VERSION 5.7 ;
  NAMESCASESENSITIVE ON ;
  NOWIREEXTENSIONATPIN ON ;
  DIVIDERCHAR "/" ;
  BUSBITCHARS "[]" ;
UNITS
  DATABASE MICRONS 200 ;
END UNITS

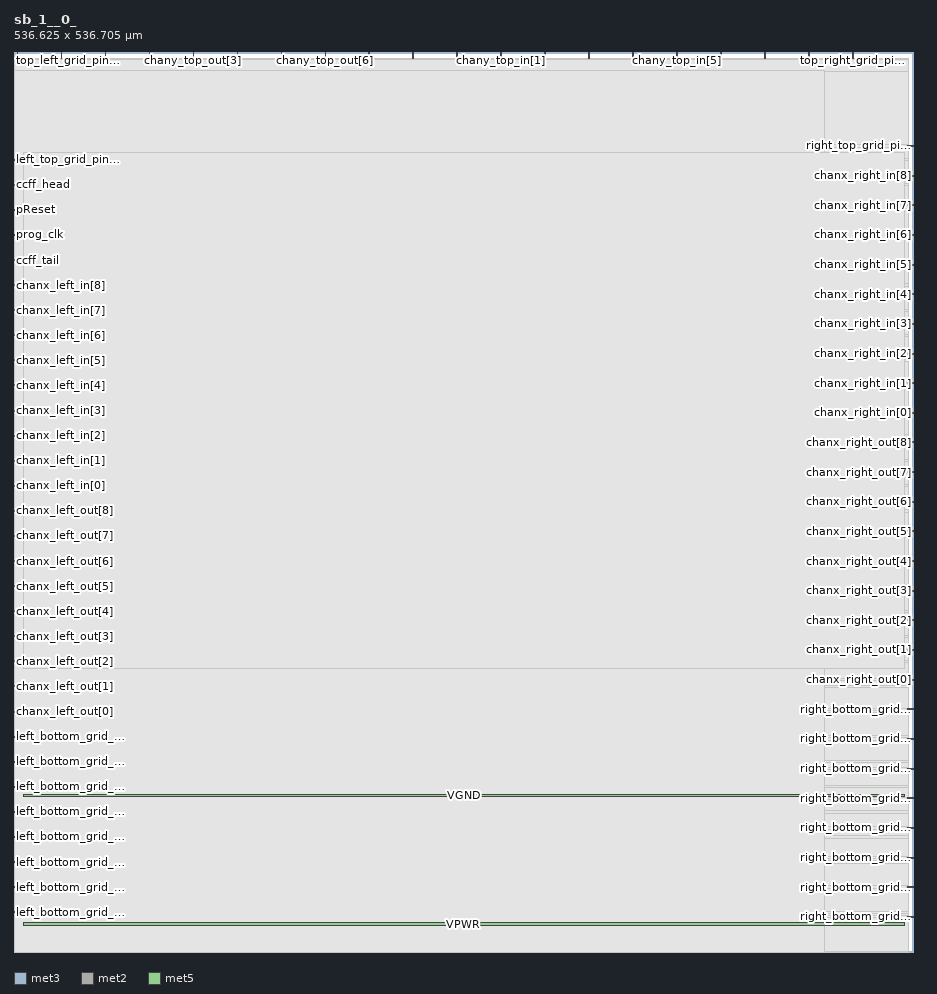
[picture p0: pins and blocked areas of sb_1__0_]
MACRO sb_1__0_
  CLASS BLOCK ;
  FOREIGN sb_1__0_ ;
  ORIGIN 0.000 0.000 ;
  SIZE 536.625 BY 536.705 ;
  PIN left_bottom_grid_pin_1_
    DIRECTION INPUT ;
    PORT
      LAYER met3 ;
        RECT 0.000 23.400 4.000 24.000 ;
    END
  END left_bottom_grid_pin_1_
  PIN left_bottom_grid_pin_3_
    DIRECTION INPUT ;
    PORT
      LAYER met3 ;
        RECT 0.000 38.360 4.000 38.960 ;
    END
  END left_bottom_grid_pin_3_
  PIN left_bottom_grid_pin_5_
    DIRECTION INPUT ;
    PORT
      LAYER met3 ;
        RECT 0.000 53.320 4.000 53.920 ;
    END
  END left_bottom_grid_pin_5_
  PIN left_bottom_grid_pin_7_
    DIRECTION INPUT ;
    PORT
      LAYER met3 ;
        RECT 0.000 68.280 4.000 68.880 ;
    END
  END left_bottom_grid_pin_7_
  PIN left_bottom_grid_pin_9_
    DIRECTION INPUT ;
    PORT
      LAYER met3 ;
        RECT 0.000 83.240 4.000 83.840 ;
    END
  END left_bottom_grid_pin_9_
  PIN left_bottom_grid_pin_11_
    DIRECTION INPUT ;
    PORT
      LAYER met3 ;
        RECT 0.000 98.200 4.000 98.800 ;
    END
  END left_bottom_grid_pin_11_
  PIN left_bottom_grid_pin_13_
    DIRECTION INPUT ;
    PORT
      LAYER met3 ;
        RECT 0.000 113.160 4.000 113.760 ;
    END
  END left_bottom_grid_pin_13_
  PIN left_bottom_grid_pin_15_
    DIRECTION INPUT ;
    PORT
      LAYER met3 ;
        RECT 0.000 128.120 4.000 128.720 ;
    END
  END left_bottom_grid_pin_15_
  PIN chanx_left_out[0]
    DIRECTION OUTPUT TRISTATE ;
    PORT
      LAYER met3 ;
        RECT 0.000 143.080 4.000 143.680 ;
    END
  END chanx_left_out[0]
  PIN chanx_left_out[1]
    DIRECTION OUTPUT TRISTATE ;
    PORT
      LAYER met3 ;
        RECT 0.000 158.040 4.000 158.640 ;
    END
  END chanx_left_out[1]
  PIN chanx_left_out[2]
    DIRECTION OUTPUT TRISTATE ;
    PORT
      LAYER met3 ;
        RECT 0.000 173.000 4.000 173.600 ;
    END
  END chanx_left_out[2]
  PIN chanx_left_out[3]
    DIRECTION OUTPUT TRISTATE ;
    PORT
      LAYER met3 ;
        RECT 0.000 187.960 4.000 188.560 ;
    END
  END chanx_left_out[3]
  PIN chanx_left_out[4]
    DIRECTION OUTPUT TRISTATE ;
    PORT
      LAYER met3 ;
        RECT 0.000 202.920 4.000 203.520 ;
    END
  END chanx_left_out[4]
  PIN chanx_left_out[5]
    DIRECTION OUTPUT TRISTATE ;
    PORT
      LAYER met3 ;
        RECT 0.000 217.880 4.000 218.480 ;
    END
  END chanx_left_out[5]
  PIN chanx_left_out[6]
    DIRECTION OUTPUT TRISTATE ;
    PORT
      LAYER met3 ;
        RECT 0.000 232.840 4.000 233.440 ;
    END
  END chanx_left_out[6]
  PIN chanx_left_out[7]
    DIRECTION OUTPUT TRISTATE ;
    PORT
      LAYER met3 ;
        RECT 0.000 247.800 4.000 248.400 ;
    END
  END chanx_left_out[7]
  PIN chanx_left_out[8]
    DIRECTION OUTPUT TRISTATE ;
    PORT
      LAYER met3 ;
        RECT 0.000 262.760 4.000 263.360 ;
    END
  END chanx_left_out[8]
  PIN chanx_left_in[0]
    DIRECTION INPUT ;
    PORT
      LAYER met3 ;
        RECT 0.000 277.720 4.000 278.320 ;
    END
  END chanx_left_in[0]
  PIN chanx_left_in[1]
    DIRECTION INPUT ;
    PORT
      LAYER met3 ;
        RECT 0.000 292.680 4.000 293.280 ;
    END
  END chanx_left_in[1]
  PIN chanx_left_in[2]
    DIRECTION INPUT ;
    PORT
      LAYER met3 ;
        RECT 0.000 307.640 4.000 308.240 ;
    END
  END chanx_left_in[2]
  PIN chanx_left_in[3]
    DIRECTION INPUT ;
    PORT
      LAYER met3 ;
        RECT 0.000 322.600 4.000 323.200 ;
    END
  END chanx_left_in[3]
  PIN chanx_left_in[4]
    DIRECTION INPUT ;
    PORT
      LAYER met3 ;
        RECT 0.000 337.560 4.000 338.160 ;
    END
  END chanx_left_in[4]
  PIN chanx_left_in[5]
    DIRECTION INPUT ;
    PORT
      LAYER met3 ;
        RECT 0.000 352.520 4.000 353.120 ;
    END
  END chanx_left_in[5]
  PIN chanx_left_in[6]
    DIRECTION INPUT ;
    PORT
      LAYER met3 ;
        RECT 0.000 367.480 4.000 368.080 ;
    END
  END chanx_left_in[6]
  PIN chanx_left_in[7]
    DIRECTION INPUT ;
    PORT
      LAYER met3 ;
        RECT 0.000 382.440 4.000 383.040 ;
    END
  END chanx_left_in[7]
  PIN chanx_left_in[8]
    DIRECTION INPUT ;
    PORT
      LAYER met3 ;
        RECT 0.000 397.400 4.000 398.000 ;
    END
  END chanx_left_in[8]
  PIN ccff_tail
    DIRECTION OUTPUT TRISTATE ;
    PORT
      LAYER met3 ;
        RECT 0.000 412.360 4.000 412.960 ;
    END
  END ccff_tail
  PIN prog_clk
    DIRECTION INPUT ;
    PORT
      LAYER met3 ;
        RECT 0.000 427.320 4.000 427.920 ;
    END
  END prog_clk
  PIN pReset
    DIRECTION INPUT ;
    PORT
      LAYER met3 ;
        RECT 0.000 442.280 4.000 442.880 ;
    END
  END pReset
  PIN ccff_head
    DIRECTION INPUT ;
    PORT
      LAYER met3 ;
        RECT 0.000 457.240 4.000 457.840 ;
    END
  END ccff_head
  PIN left_top_grid_pin_10_
    DIRECTION OUTPUT TRISTATE ;
    PORT
      LAYER met3 ;
        RECT 0.000 472.200 4.000 472.800 ;
    END
  END left_top_grid_pin_10_
  PIN top_left_grid_pin_13_
    DIRECTION INPUT ;
    PORT
      LAYER met2 ;
        RECT 1.930 532.705 2.210 536.705 ;
    END
  END top_left_grid_pin_13_
  PIN chany_top_out[0]
    DIRECTION OUTPUT TRISTATE ;
    PORT
      LAYER met2 ;
        RECT 28.150 532.705 28.430 536.705 ;
    END
  END chany_top_out[0]
  PIN chany_top_out[1]
    DIRECTION OUTPUT TRISTATE ;
    PORT
      LAYER met2 ;
        RECT 54.370 532.705 54.650 536.705 ;
    END
  END chany_top_out[1]
  PIN chany_top_out[2]
    DIRECTION OUTPUT TRISTATE ;
    PORT
      LAYER met2 ;
        RECT 80.590 532.705 80.870 536.705 ;
    END
  END chany_top_out[2]
  PIN chany_top_out[3]
    DIRECTION OUTPUT TRISTATE ;
    PORT
      LAYER met2 ;
        RECT 106.810 532.705 107.090 536.705 ;
    END
  END chany_top_out[3]
  PIN chany_top_out[4]
    DIRECTION OUTPUT TRISTATE ;
    PORT
      LAYER met2 ;
        RECT 133.030 532.705 133.310 536.705 ;
    END
  END chany_top_out[4]
  PIN chany_top_out[5]
    DIRECTION OUTPUT TRISTATE ;
    PORT
      LAYER met2 ;
        RECT 159.250 532.705 159.530 536.705 ;
    END
  END chany_top_out[5]
  PIN chany_top_out[6]
    DIRECTION OUTPUT TRISTATE ;
    PORT
      LAYER met2 ;
        RECT 185.470 532.705 185.750 536.705 ;
    END
  END chany_top_out[6]
  PIN chany_top_out[7]
    DIRECTION OUTPUT TRISTATE ;
    PORT
      LAYER met2 ;
        RECT 211.690 532.705 211.970 536.705 ;
    END
  END chany_top_out[7]
  PIN chany_top_out[8]
    DIRECTION OUTPUT TRISTATE ;
    PORT
      LAYER met2 ;
        RECT 237.910 532.705 238.190 536.705 ;
    END
  END chany_top_out[8]
  PIN chany_top_in[0]
    DIRECTION INPUT ;
    PORT
      LAYER met2 ;
        RECT 264.130 532.705 264.410 536.705 ;
    END
  END chany_top_in[0]
  PIN chany_top_in[1]
    DIRECTION INPUT ;
    PORT
      LAYER met2 ;
        RECT 290.350 532.705 290.630 536.705 ;
    END
  END chany_top_in[1]
  PIN chany_top_in[2]
    DIRECTION INPUT ;
    PORT
      LAYER met2 ;
        RECT 316.570 532.705 316.850 536.705 ;
    END
  END chany_top_in[2]
  PIN chany_top_in[3]
    DIRECTION INPUT ;
    PORT
      LAYER met2 ;
        RECT 342.790 532.705 343.070 536.705 ;
    END
  END chany_top_in[3]
  PIN chany_top_in[4]
    DIRECTION INPUT ;
    PORT
      LAYER met2 ;
        RECT 369.010 532.705 369.290 536.705 ;
    END
  END chany_top_in[4]
  PIN chany_top_in[5]
    DIRECTION INPUT ;
    PORT
      LAYER met2 ;
        RECT 395.230 532.705 395.510 536.705 ;
    END
  END chany_top_in[5]
  PIN chany_top_in[6]
    DIRECTION INPUT ;
    PORT
      LAYER met2 ;
        RECT 421.450 532.705 421.730 536.705 ;
    END
  END chany_top_in[6]
  PIN chany_top_in[7]
    DIRECTION INPUT ;
    PORT
      LAYER met2 ;
        RECT 447.670 532.705 447.950 536.705 ;
    END
  END chany_top_in[7]
  PIN chany_top_in[8]
    DIRECTION INPUT ;
    PORT
      LAYER met2 ;
        RECT 473.890 532.705 474.170 536.705 ;
    END
  END chany_top_in[8]
  PIN top_right_grid_pin_11_
    DIRECTION INPUT ;
    PORT
      LAYER met2 ;
        RECT 500.110 532.705 500.390 536.705 ;
    END
  END top_right_grid_pin_11_
  PIN right_bottom_grid_pin_1_
    DIRECTION INPUT ;
    PORT
      LAYER met3 ;
        RECT 532.625 20.680 536.625 21.280 ;
    END
  END right_bottom_grid_pin_1_
  PIN right_bottom_grid_pin_3_
    DIRECTION INPUT ;
    PORT
      LAYER met3 ;
        RECT 532.625 38.360 536.625 38.960 ;
    END
  END right_bottom_grid_pin_3_
  PIN right_bottom_grid_pin_5_
    DIRECTION INPUT ;
    PORT
      LAYER met3 ;
        RECT 532.625 56.040 536.625 56.640 ;
    END
  END right_bottom_grid_pin_5_
  PIN right_bottom_grid_pin_7_
    DIRECTION INPUT ;
    PORT
      LAYER met3 ;
        RECT 532.625 73.720 536.625 74.320 ;
    END
  END right_bottom_grid_pin_7_
  PIN right_bottom_grid_pin_9_
    DIRECTION INPUT ;
    PORT
      LAYER met3 ;
        RECT 532.625 91.400 536.625 92.000 ;
    END
  END right_bottom_grid_pin_9_
  PIN right_bottom_grid_pin_11_
    DIRECTION INPUT ;
    PORT
      LAYER met3 ;
        RECT 532.625 109.080 536.625 109.680 ;
    END
  END right_bottom_grid_pin_11_
  PIN right_bottom_grid_pin_13_
    DIRECTION INPUT ;
    PORT
      LAYER met3 ;
        RECT 532.625 126.760 536.625 127.360 ;
    END
  END right_bottom_grid_pin_13_
  PIN right_bottom_grid_pin_15_
    DIRECTION INPUT ;
    PORT
      LAYER met3 ;
        RECT 532.625 144.440 536.625 145.040 ;
    END
  END right_bottom_grid_pin_15_
  PIN chanx_right_out[0]
    DIRECTION OUTPUT TRISTATE ;
    PORT
      LAYER met3 ;
        RECT 532.625 162.120 536.625 162.720 ;
    END
  END chanx_right_out[0]
  PIN chanx_right_out[1]
    DIRECTION OUTPUT TRISTATE ;
    PORT
      LAYER met3 ;
        RECT 532.625 179.800 536.625 180.400 ;
    END
  END chanx_right_out[1]
  PIN chanx_right_out[2]
    DIRECTION OUTPUT TRISTATE ;
    PORT
      LAYER met3 ;
        RECT 532.625 197.480 536.625 198.080 ;
    END
  END chanx_right_out[2]
  PIN chanx_right_out[3]
    DIRECTION OUTPUT TRISTATE ;
    PORT
      LAYER met3 ;
        RECT 532.625 215.160 536.625 215.760 ;
    END
  END chanx_right_out[3]
  PIN chanx_right_out[4]
    DIRECTION OUTPUT TRISTATE ;
    PORT
      LAYER met3 ;
        RECT 532.625 232.840 536.625 233.440 ;
    END
  END chanx_right_out[4]
  PIN chanx_right_out[5]
    DIRECTION OUTPUT TRISTATE ;
    PORT
      LAYER met3 ;
        RECT 532.625 250.520 536.625 251.120 ;
    END
  END chanx_right_out[5]
  PIN chanx_right_out[6]
    DIRECTION OUTPUT TRISTATE ;
    PORT
      LAYER met3 ;
        RECT 532.625 268.200 536.625 268.800 ;
    END
  END chanx_right_out[6]
  PIN chanx_right_out[7]
    DIRECTION OUTPUT TRISTATE ;
    PORT
      LAYER met3 ;
        RECT 532.625 285.880 536.625 286.480 ;
    END
  END chanx_right_out[7]
  PIN chanx_right_out[8]
    DIRECTION OUTPUT TRISTATE ;
    PORT
      LAYER met3 ;
        RECT 532.625 303.560 536.625 304.160 ;
    END
  END chanx_right_out[8]
  PIN chanx_right_in[0]
    DIRECTION INPUT ;
    PORT
      LAYER met3 ;
        RECT 532.625 321.240 536.625 321.840 ;
    END
  END chanx_right_in[0]
  PIN chanx_right_in[1]
    DIRECTION INPUT ;
    PORT
      LAYER met3 ;
        RECT 532.625 338.920 536.625 339.520 ;
    END
  END chanx_right_in[1]
  PIN chanx_right_in[2]
    DIRECTION INPUT ;
    PORT
      LAYER met3 ;
        RECT 532.625 356.600 536.625 357.200 ;
    END
  END chanx_right_in[2]
  PIN chanx_right_in[3]
    DIRECTION INPUT ;
    PORT
      LAYER met3 ;
        RECT 532.625 374.280 536.625 374.880 ;
    END
  END chanx_right_in[3]
  PIN chanx_right_in[4]
    DIRECTION INPUT ;
    PORT
      LAYER met3 ;
        RECT 532.625 391.960 536.625 392.560 ;
    END
  END chanx_right_in[4]
  PIN chanx_right_in[5]
    DIRECTION INPUT ;
    PORT
      LAYER met3 ;
        RECT 532.625 409.640 536.625 410.240 ;
    END
  END chanx_right_in[5]
  PIN chanx_right_in[6]
    DIRECTION INPUT ;
    PORT
      LAYER met3 ;
        RECT 532.625 427.320 536.625 427.920 ;
    END
  END chanx_right_in[6]
  PIN chanx_right_in[7]
    DIRECTION INPUT ;
    PORT
      LAYER met3 ;
        RECT 532.625 445.000 536.625 445.600 ;
    END
  END chanx_right_in[7]
  PIN chanx_right_in[8]
    DIRECTION INPUT ;
    PORT
      LAYER met3 ;
        RECT 532.625 462.680 536.625 463.280 ;
    END
  END chanx_right_in[8]
  PIN right_top_grid_pin_10_
    DIRECTION OUTPUT TRISTATE ;
    PORT
      LAYER met3 ;
        RECT 532.625 480.360 536.625 480.960 ;
    END
  END right_top_grid_pin_10_
  PIN VPWR
    DIRECTION INPUT ;
    USE POWER ;
    PORT
      LAYER met5 ;
        RECT 5.520 15.850 530.840 17.450 ;
    END
  END VPWR
  PIN VGND
    DIRECTION INPUT ;
    USE GROUND ;
    PORT
      LAYER met5 ;
        RECT 5.520 92.440 530.840 94.040 ;
    END
  END VGND
  OBS
      LAYER li1 ;
        RECT 5.520 0.155 530.840 525.285 ;
      LAYER met1 ;
        RECT 0.530 0.000 533.070 532.980 ;
      LAYER met2 ;
        RECT 0.090 532.425 1.650 533.090 ;
        RECT 2.490 532.425 27.870 533.090 ;
        RECT 28.710 532.425 54.090 533.090 ;
        RECT 54.930 532.425 80.310 533.090 ;
        RECT 81.150 532.425 106.530 533.090 ;
        RECT 107.370 532.425 132.750 533.090 ;
        RECT 133.590 532.425 158.970 533.090 ;
        RECT 159.810 532.425 185.190 533.090 ;
        RECT 186.030 532.425 211.410 533.090 ;
        RECT 212.250 532.425 237.630 533.090 ;
        RECT 238.470 532.425 263.850 533.090 ;
        RECT 264.690 532.425 290.070 533.090 ;
        RECT 290.910 532.425 316.290 533.090 ;
        RECT 317.130 532.425 342.510 533.090 ;
        RECT 343.350 532.425 368.730 533.090 ;
        RECT 369.570 532.425 394.950 533.090 ;
        RECT 395.790 532.425 421.170 533.090 ;
        RECT 422.010 532.425 447.390 533.090 ;
        RECT 448.230 532.425 473.610 533.090 ;
        RECT 474.450 532.425 499.830 533.090 ;
        RECT 500.670 532.425 533.510 533.090 ;
        RECT 0.090 0.000 533.510 532.425 ;
      LAYER met3 ;
        RECT 0.065 481.360 533.290 525.365 ;
        RECT 0.065 479.960 532.225 481.360 ;
        RECT 0.065 473.200 533.290 479.960 ;
        RECT 4.400 471.800 533.290 473.200 ;
        RECT 0.065 463.680 533.290 471.800 ;
        RECT 0.065 462.280 532.225 463.680 ;
        RECT 0.065 458.240 533.290 462.280 ;
        RECT 4.400 456.840 533.290 458.240 ;
        RECT 0.065 446.000 533.290 456.840 ;
        RECT 0.065 444.600 532.225 446.000 ;
        RECT 0.065 443.280 533.290 444.600 ;
        RECT 4.400 441.880 533.290 443.280 ;
        RECT 0.065 428.320 533.290 441.880 ;
        RECT 4.400 426.920 532.225 428.320 ;
        RECT 0.065 413.360 533.290 426.920 ;
        RECT 4.400 411.960 533.290 413.360 ;
        RECT 0.065 410.640 533.290 411.960 ;
        RECT 0.065 409.240 532.225 410.640 ;
        RECT 0.065 398.400 533.290 409.240 ;
        RECT 4.400 397.000 533.290 398.400 ;
        RECT 0.065 392.960 533.290 397.000 ;
        RECT 0.065 391.560 532.225 392.960 ;
        RECT 0.065 383.440 533.290 391.560 ;
        RECT 4.400 382.040 533.290 383.440 ;
        RECT 0.065 375.280 533.290 382.040 ;
        RECT 0.065 373.880 532.225 375.280 ;
        RECT 0.065 368.480 533.290 373.880 ;
        RECT 4.400 367.080 533.290 368.480 ;
        RECT 0.065 357.600 533.290 367.080 ;
        RECT 0.065 356.200 532.225 357.600 ;
        RECT 0.065 353.520 533.290 356.200 ;
        RECT 4.400 352.120 533.290 353.520 ;
        RECT 0.065 339.920 533.290 352.120 ;
        RECT 0.065 338.560 532.225 339.920 ;
        RECT 4.400 338.520 532.225 338.560 ;
        RECT 4.400 337.160 533.290 338.520 ;
        RECT 0.065 323.600 533.290 337.160 ;
        RECT 4.400 322.240 533.290 323.600 ;
        RECT 4.400 322.200 532.225 322.240 ;
        RECT 0.065 320.840 532.225 322.200 ;
        RECT 0.065 308.640 533.290 320.840 ;
        RECT 4.400 307.240 533.290 308.640 ;
        RECT 0.065 304.560 533.290 307.240 ;
        RECT 0.065 303.160 532.225 304.560 ;
        RECT 0.065 293.680 533.290 303.160 ;
        RECT 4.400 292.280 533.290 293.680 ;
        RECT 0.065 286.880 533.290 292.280 ;
        RECT 0.065 285.480 532.225 286.880 ;
        RECT 0.065 278.720 533.290 285.480 ;
        RECT 4.400 277.320 533.290 278.720 ;
        RECT 0.065 269.200 533.290 277.320 ;
        RECT 0.065 267.800 532.225 269.200 ;
        RECT 0.065 263.760 533.290 267.800 ;
        RECT 4.400 262.360 533.290 263.760 ;
        RECT 0.065 251.520 533.290 262.360 ;
        RECT 0.065 250.120 532.225 251.520 ;
        RECT 0.065 248.800 533.290 250.120 ;
        RECT 4.400 247.400 533.290 248.800 ;
        RECT 0.065 233.840 533.290 247.400 ;
        RECT 4.400 232.440 532.225 233.840 ;
        RECT 0.065 218.880 533.290 232.440 ;
        RECT 4.400 217.480 533.290 218.880 ;
        RECT 0.065 216.160 533.290 217.480 ;
        RECT 0.065 214.760 532.225 216.160 ;
        RECT 0.065 203.920 533.290 214.760 ;
        RECT 4.400 202.520 533.290 203.920 ;
        RECT 0.065 198.480 533.290 202.520 ;
        RECT 0.065 197.080 532.225 198.480 ;
        RECT 0.065 188.960 533.290 197.080 ;
        RECT 4.400 187.560 533.290 188.960 ;
        RECT 0.065 180.800 533.290 187.560 ;
        RECT 0.065 179.400 532.225 180.800 ;
        RECT 0.065 174.000 533.290 179.400 ;
        RECT 4.400 172.600 533.290 174.000 ;
        RECT 0.065 163.120 533.290 172.600 ;
        RECT 0.065 161.720 532.225 163.120 ;
        RECT 0.065 159.040 533.290 161.720 ;
        RECT 4.400 157.640 533.290 159.040 ;
        RECT 0.065 145.440 533.290 157.640 ;
        RECT 0.065 144.080 532.225 145.440 ;
        RECT 4.400 144.040 532.225 144.080 ;
        RECT 4.400 142.680 533.290 144.040 ;
        RECT 0.065 129.120 533.290 142.680 ;
        RECT 4.400 127.760 533.290 129.120 ;
        RECT 4.400 127.720 532.225 127.760 ;
        RECT 0.065 126.360 532.225 127.720 ;
        RECT 0.065 114.160 533.290 126.360 ;
        RECT 4.400 112.760 533.290 114.160 ;
        RECT 0.065 110.080 533.290 112.760 ;
        RECT 0.065 108.680 532.225 110.080 ;
        RECT 0.065 99.200 533.290 108.680 ;
        RECT 4.400 97.800 533.290 99.200 ;
        RECT 0.065 92.400 533.290 97.800 ;
        RECT 0.065 91.000 532.225 92.400 ;
        RECT 0.065 84.240 533.290 91.000 ;
        RECT 4.400 82.840 533.290 84.240 ;
        RECT 0.065 74.720 533.290 82.840 ;
        RECT 0.065 73.320 532.225 74.720 ;
        RECT 0.065 69.280 533.290 73.320 ;
        RECT 4.400 67.880 533.290 69.280 ;
        RECT 0.065 57.040 533.290 67.880 ;
        RECT 0.065 55.640 532.225 57.040 ;
        RECT 0.065 54.320 533.290 55.640 ;
        RECT 4.400 52.920 533.290 54.320 ;
        RECT 0.065 39.360 533.290 52.920 ;
        RECT 4.400 37.960 532.225 39.360 ;
        RECT 0.065 24.400 533.290 37.960 ;
        RECT 4.400 23.000 533.290 24.400 ;
        RECT 0.065 21.680 533.290 23.000 ;
        RECT 0.065 20.280 532.225 21.680 ;
        RECT 0.065 0.075 533.290 20.280 ;
      LAYER met4 ;
        RECT 0.295 0.000 483.440 525.440 ;
      LAYER met5 ;
        RECT 5.520 169.030 530.840 476.990 ;
  END
END sb_1__0_
END LIBRARY

